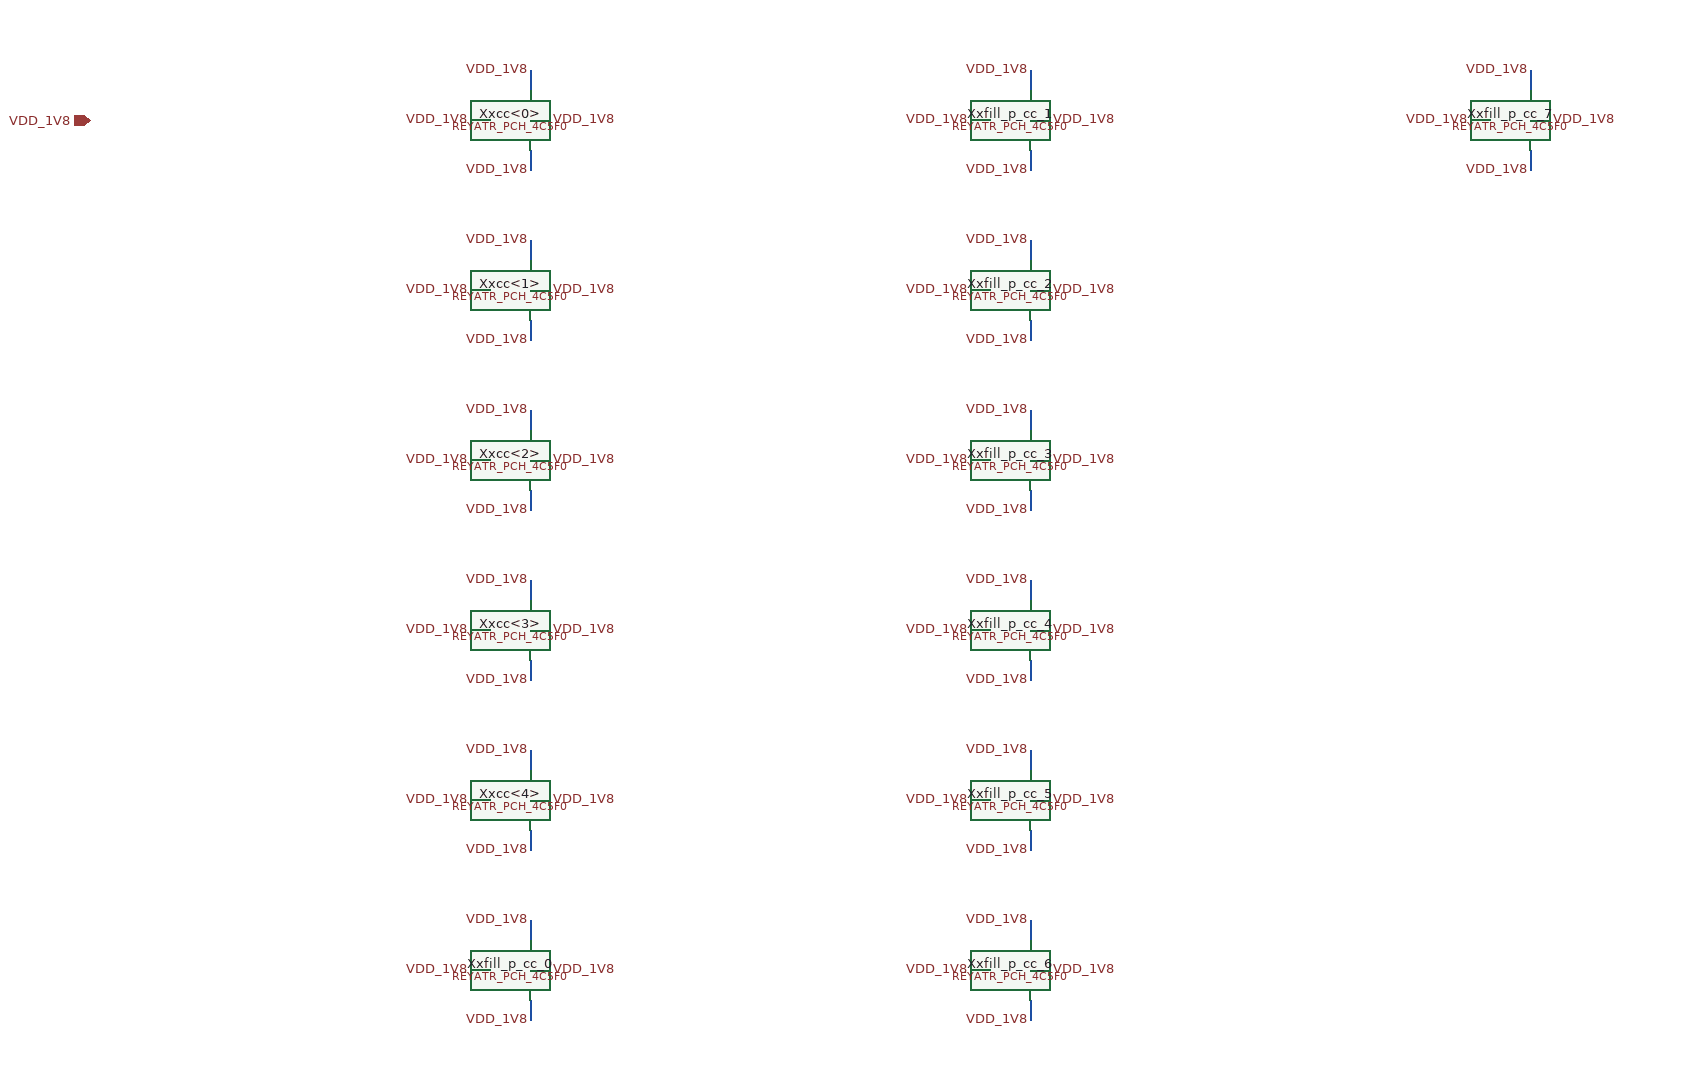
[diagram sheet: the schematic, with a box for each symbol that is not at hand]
v {xschem version=3.0.0 file_version=1.2 }
G {}
K {}
V {}
S {}
E {}
C {devices/iopin.sym} 0 0 0 0 {name=p0 lab=VDD_1V8}
C {REY_ATR_SKY130A/REYATR_PCH_4C5F0.sym} 400 0 0 0 {name=Xxcc<0>}
N 440.0 50.0 440.0 30.0 {lab=VDD_1V8}
C {devices/lab_pin.sym} 440.0 50.0 1 0 {name=l0 sig_type=std_logic lab=VDD_1V8 }
N 380.0 0.0 400.0 0.0 {lab=VDD_1V8}
C {devices/lab_pin.sym} 380.0 0.0 0 0 {name=l1 sig_type=std_logic lab=VDD_1V8 }
N 440.0 -50.0 440.0 -30.0 {lab=VDD_1V8}
C {devices/lab_pin.sym} 440.0 -50.0 3 0 {name=l2 sig_type=std_logic lab=VDD_1V8 }
N 460.0 0.0 440.0 0.0 {lab=VDD_1V8}
C {devices/lab_pin.sym} 460.0 0.0 2 0 {name=l3 sig_type=std_logic lab=VDD_1V8 }
C {REY_ATR_SKY130A/REYATR_PCH_4C5F0.sym} 400 170.0 0 0 {name=Xxcc<1>}
N 440.0 220.0 440.0 200.0 {lab=VDD_1V8}
C {devices/lab_pin.sym} 440.0 220.0 1 0 {name=l4 sig_type=std_logic lab=VDD_1V8 }
N 380.0 170.0 400.0 170.0 {lab=VDD_1V8}
C {devices/lab_pin.sym} 380.0 170.0 0 0 {name=l5 sig_type=std_logic lab=VDD_1V8 }
N 440.0 120.0 440.0 140.0 {lab=VDD_1V8}
C {devices/lab_pin.sym} 440.0 120.0 3 0 {name=l6 sig_type=std_logic lab=VDD_1V8 }
N 460.0 170.0 440.0 170.0 {lab=VDD_1V8}
C {devices/lab_pin.sym} 460.0 170.0 2 0 {name=l7 sig_type=std_logic lab=VDD_1V8 }
C {REY_ATR_SKY130A/REYATR_PCH_4C5F0.sym} 400 340.0 0 0 {name=Xxcc<2>}
N 440.0 390.0 440.0 370.0 {lab=VDD_1V8}
C {devices/lab_pin.sym} 440.0 390.0 1 0 {name=l8 sig_type=std_logic lab=VDD_1V8 }
N 380.0 340.0 400.0 340.0 {lab=VDD_1V8}
C {devices/lab_pin.sym} 380.0 340.0 0 0 {name=l9 sig_type=std_logic lab=VDD_1V8 }
N 440.0 290.0 440.0 310.0 {lab=VDD_1V8}
C {devices/lab_pin.sym} 440.0 290.0 3 0 {name=l10 sig_type=std_logic lab=VDD_1V8 }
N 460.0 340.0 440.0 340.0 {lab=VDD_1V8}
C {devices/lab_pin.sym} 460.0 340.0 2 0 {name=l11 sig_type=std_logic lab=VDD_1V8 }
C {REY_ATR_SKY130A/REYATR_PCH_4C5F0.sym} 400 510.0 0 0 {name=Xxcc<3>}
N 440.0 560.0 440.0 540.0 {lab=VDD_1V8}
C {devices/lab_pin.sym} 440.0 560.0 1 0 {name=l12 sig_type=std_logic lab=VDD_1V8 }
N 380.0 510.0 400.0 510.0 {lab=VDD_1V8}
C {devices/lab_pin.sym} 380.0 510.0 0 0 {name=l13 sig_type=std_logic lab=VDD_1V8 }
N 440.0 460.0 440.0 480.0 {lab=VDD_1V8}
C {devices/lab_pin.sym} 440.0 460.0 3 0 {name=l14 sig_type=std_logic lab=VDD_1V8 }
N 460.0 510.0 440.0 510.0 {lab=VDD_1V8}
C {devices/lab_pin.sym} 460.0 510.0 2 0 {name=l15 sig_type=std_logic lab=VDD_1V8 }
C {REY_ATR_SKY130A/REYATR_PCH_4C5F0.sym} 400 680.0 0 0 {name=Xxcc<4>}
N 440.0 730.0 440.0 710.0 {lab=VDD_1V8}
C {devices/lab_pin.sym} 440.0 730.0 1 0 {name=l16 sig_type=std_logic lab=VDD_1V8 }
N 380.0 680.0 400.0 680.0 {lab=VDD_1V8}
C {devices/lab_pin.sym} 380.0 680.0 0 0 {name=l17 sig_type=std_logic lab=VDD_1V8 }
N 440.0 630.0 440.0 650.0 {lab=VDD_1V8}
C {devices/lab_pin.sym} 440.0 630.0 3 0 {name=l18 sig_type=std_logic lab=VDD_1V8 }
N 460.0 680.0 440.0 680.0 {lab=VDD_1V8}
C {devices/lab_pin.sym} 460.0 680.0 2 0 {name=l19 sig_type=std_logic lab=VDD_1V8 }
C {REY_ATR_SKY130A/REYATR_PCH_4C5F0.sym} 400 850.0 0 0 {name=Xxfill_p_cc_0}
N 440.0 900.0 440.0 880.0 {lab=VDD_1V8}
C {devices/lab_pin.sym} 440.0 900.0 1 0 {name=l20 sig_type=std_logic lab=VDD_1V8 }
N 380.0 850.0 400.0 850.0 {lab=VDD_1V8}
C {devices/lab_pin.sym} 380.0 850.0 0 0 {name=l21 sig_type=std_logic lab=VDD_1V8 }
N 440.0 800.0 440.0 820.0 {lab=VDD_1V8}
C {devices/lab_pin.sym} 440.0 800.0 3 0 {name=l22 sig_type=std_logic lab=VDD_1V8 }
N 460.0 850.0 440.0 850.0 {lab=VDD_1V8}
C {devices/lab_pin.sym} 460.0 850.0 2 0 {name=l23 sig_type=std_logic lab=VDD_1V8 }
C {REY_ATR_SKY130A/REYATR_PCH_4C5F0.sym} 900 0 0 0 {name=Xxfill_p_cc_1}
N 940.0 50.0 940.0 30.0 {lab=VDD_1V8}
C {devices/lab_pin.sym} 940.0 50.0 1 0 {name=l24 sig_type=std_logic lab=VDD_1V8 }
N 880.0 0.0 900.0 0.0 {lab=VDD_1V8}
C {devices/lab_pin.sym} 880.0 0.0 0 0 {name=l25 sig_type=std_logic lab=VDD_1V8 }
N 940.0 -50.0 940.0 -30.0 {lab=VDD_1V8}
C {devices/lab_pin.sym} 940.0 -50.0 3 0 {name=l26 sig_type=std_logic lab=VDD_1V8 }
N 960.0 0.0 940.0 0.0 {lab=VDD_1V8}
C {devices/lab_pin.sym} 960.0 0.0 2 0 {name=l27 sig_type=std_logic lab=VDD_1V8 }
C {REY_ATR_SKY130A/REYATR_PCH_4C5F0.sym} 900 170.0 0 0 {name=Xxfill_p_cc_2}
N 940.0 220.0 940.0 200.0 {lab=VDD_1V8}
C {devices/lab_pin.sym} 940.0 220.0 1 0 {name=l28 sig_type=std_logic lab=VDD_1V8 }
N 880.0 170.0 900.0 170.0 {lab=VDD_1V8}
C {devices/lab_pin.sym} 880.0 170.0 0 0 {name=l29 sig_type=std_logic lab=VDD_1V8 }
N 940.0 120.0 940.0 140.0 {lab=VDD_1V8}
C {devices/lab_pin.sym} 940.0 120.0 3 0 {name=l30 sig_type=std_logic lab=VDD_1V8 }
N 960.0 170.0 940.0 170.0 {lab=VDD_1V8}
C {devices/lab_pin.sym} 960.0 170.0 2 0 {name=l31 sig_type=std_logic lab=VDD_1V8 }
C {REY_ATR_SKY130A/REYATR_PCH_4C5F0.sym} 900 340.0 0 0 {name=Xxfill_p_cc_3}
N 940.0 390.0 940.0 370.0 {lab=VDD_1V8}
C {devices/lab_pin.sym} 940.0 390.0 1 0 {name=l32 sig_type=std_logic lab=VDD_1V8 }
N 880.0 340.0 900.0 340.0 {lab=VDD_1V8}
C {devices/lab_pin.sym} 880.0 340.0 0 0 {name=l33 sig_type=std_logic lab=VDD_1V8 }
N 940.0 290.0 940.0 310.0 {lab=VDD_1V8}
C {devices/lab_pin.sym} 940.0 290.0 3 0 {name=l34 sig_type=std_logic lab=VDD_1V8 }
N 960.0 340.0 940.0 340.0 {lab=VDD_1V8}
C {devices/lab_pin.sym} 960.0 340.0 2 0 {name=l35 sig_type=std_logic lab=VDD_1V8 }
C {REY_ATR_SKY130A/REYATR_PCH_4C5F0.sym} 900 510.0 0 0 {name=Xxfill_p_cc_4}
N 940.0 560.0 940.0 540.0 {lab=VDD_1V8}
C {devices/lab_pin.sym} 940.0 560.0 1 0 {name=l36 sig_type=std_logic lab=VDD_1V8 }
N 880.0 510.0 900.0 510.0 {lab=VDD_1V8}
C {devices/lab_pin.sym} 880.0 510.0 0 0 {name=l37 sig_type=std_logic lab=VDD_1V8 }
N 940.0 460.0 940.0 480.0 {lab=VDD_1V8}
C {devices/lab_pin.sym} 940.0 460.0 3 0 {name=l38 sig_type=std_logic lab=VDD_1V8 }
N 960.0 510.0 940.0 510.0 {lab=VDD_1V8}
C {devices/lab_pin.sym} 960.0 510.0 2 0 {name=l39 sig_type=std_logic lab=VDD_1V8 }
C {REY_ATR_SKY130A/REYATR_PCH_4C5F0.sym} 900 680.0 0 0 {name=Xxfill_p_cc_5}
N 940.0 730.0 940.0 710.0 {lab=VDD_1V8}
C {devices/lab_pin.sym} 940.0 730.0 1 0 {name=l40 sig_type=std_logic lab=VDD_1V8 }
N 880.0 680.0 900.0 680.0 {lab=VDD_1V8}
C {devices/lab_pin.sym} 880.0 680.0 0 0 {name=l41 sig_type=std_logic lab=VDD_1V8 }
N 940.0 630.0 940.0 650.0 {lab=VDD_1V8}
C {devices/lab_pin.sym} 940.0 630.0 3 0 {name=l42 sig_type=std_logic lab=VDD_1V8 }
N 960.0 680.0 940.0 680.0 {lab=VDD_1V8}
C {devices/lab_pin.sym} 960.0 680.0 2 0 {name=l43 sig_type=std_logic lab=VDD_1V8 }
C {REY_ATR_SKY130A/REYATR_PCH_4C5F0.sym} 900 850.0 0 0 {name=Xxfill_p_cc_6}
N 940.0 900.0 940.0 880.0 {lab=VDD_1V8}
C {devices/lab_pin.sym} 940.0 900.0 1 0 {name=l44 sig_type=std_logic lab=VDD_1V8 }
N 880.0 850.0 900.0 850.0 {lab=VDD_1V8}
C {devices/lab_pin.sym} 880.0 850.0 0 0 {name=l45 sig_type=std_logic lab=VDD_1V8 }
N 940.0 800.0 940.0 820.0 {lab=VDD_1V8}
C {devices/lab_pin.sym} 940.0 800.0 3 0 {name=l46 sig_type=std_logic lab=VDD_1V8 }
N 960.0 850.0 940.0 850.0 {lab=VDD_1V8}
C {devices/lab_pin.sym} 960.0 850.0 2 0 {name=l47 sig_type=std_logic lab=VDD_1V8 }
C {REY_ATR_SKY130A/REYATR_PCH_4C5F0.sym} 1400 0 0 0 {name=Xxfill_p_cc_7}
N 1440.0 50.0 1440.0 30.0 {lab=VDD_1V8}
C {devices/lab_pin.sym} 1440.0 50.0 1 0 {name=l48 sig_type=std_logic lab=VDD_1V8 }
N 1380.0 0.0 1400.0 0.0 {lab=VDD_1V8}
C {devices/lab_pin.sym} 1380.0 0.0 0 0 {name=l49 sig_type=std_logic lab=VDD_1V8 }
N 1440.0 -50.0 1440.0 -30.0 {lab=VDD_1V8}
C {devices/lab_pin.sym} 1440.0 -50.0 3 0 {name=l50 sig_type=std_logic lab=VDD_1V8 }
N 1460.0 0.0 1440.0 0.0 {lab=VDD_1V8}
C {devices/lab_pin.sym} 1460.0 0.0 2 0 {name=l51 sig_type=std_logic lab=VDD_1V8 }
